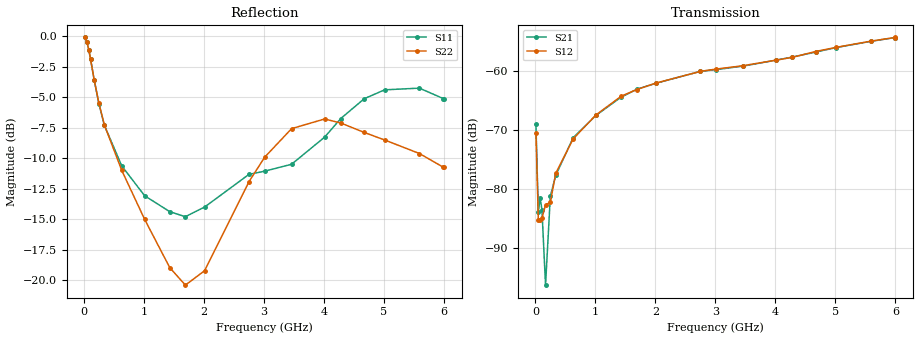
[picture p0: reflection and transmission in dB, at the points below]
!Agilent Technologies,N5230A,MY45001650,A.07.50.48
!Agilent N5230A: A.07.50.48
!Date: Saturday, July 08, 2017 15:48:11
!Correction: S11(Full 2 Port(1,2))
!S21(Full 2 Port(1,2))
!S12(Full 2 Port(1,2))
!S22(Full 2 Port(1,2))
!S2P File: Measurements: S11, S21, S12, S22:
# Hz S  dB  R 50
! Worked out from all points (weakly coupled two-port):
!   600 points, 10 MHz to 6 GHz, reference 50 ohm
!   highest |S21| = -54.43 dB at 5.99 GHz (marker M1); lowest = -96.3 dB at 170 MHz (marker M2)
!   lowest |S11| = -14.8 dB at 1.69 GHz (marker M3), VSWR 1.44, Z = 34.7 + j1.18 ohm
!   |S11| at or under -10 dB: 553.2 MHz to 3.662 GHz (3.109 GHz wide, 148 % of centre)
!   |S22| runs from -20.6 to -0.1 dB; largest |S21 - S12| = 0.00047
!   S11 on the Smith chart (normalised r, x): 10 MHz: 3, -20; 110 MHz: 0.52, -1.89; 340 MHz: 0.55, -0.54; 2.75 GHz: 0.58, +0.10; 4.28 GHz: 1.39, +1.16; 6 GHz: 2.58, -1.44
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1e7  -0.11 -5.7  -69.07 -174.8  -70.48 -81.6  -0.11 -5.7
5e7  -0.50 -26.6  -83.99 138.6  -85.29 -8.4  -0.50 -26.5
8e7  -1.13 -40.8  -81.49 137.6  -85.32 8.5  -1.12 -40.5
1.1e8  -1.91 -53.1  -83.53 99.7  -85.00 -21.4  -1.91 -52.8
1.7e8  -3.61 -73.0  -96.27 110.6  -82.67 103.9  -3.59 -72.6
2.5e8  -5.58 -92.8  -81.23 110.4  -82.28 106.8  -5.53 -92.3
3.4e8  -7.32 -110.7  -77.72 91.1  -77.37 86.9  -7.29 -108.9
6.3e8  -10.65 -147.5  -71.35 52.8  -71.55 54.3  -11.02 -142.3
1.01e9  -13.09 -172.4  -67.58 13.9  -67.50 13.8  -15.02 -165.4
1.43e9  -14.40 174.0  -64.49 -23.9  -64.34 -22.4  -18.99 -179.9
1.69e9  -14.81 174.8  -63.17 -48.4  -63.21 -47.2  -20.42 -177.7
2.01e9  -14.02 177.0  -62.14 -77.8  -62.12 -78.2  -19.24 -174.7
2.75e9  -11.34 162.4  -60.14 -148.3  -60.14 -147.9  -11.94 162.5
3.01e9  -11.08 149.1  -59.84 -172.8  -59.75 -172.8  -9.94 152.6
3.46e9  -10.51 117.0  -59.25 146.0  -59.18 146.2  -7.59 138.1
4.01e9  -8.29 64.4  -58.24 98.9  -58.24 98.9  -6.80 119.1
4.28e9  -6.76 45.4  -57.72 78.0  -57.77 78.2  -7.13 108.3
4.67e9  -5.14 25.4  -56.88 46.4  -56.78 46.2  -7.90 89.1
5.01e9  -4.41 13.6  -56.12 19.0  -56.08 18.6  -8.52 69.3
5.59e9  -4.27 -4.6  -55.06 -28.3  -55.03 -28.4  -9.63 32.5
5.99e9  -5.13 -20.0  -54.43 -55.8  -54.41 -56.0  -10.76 10.4
6e9  -5.13 -20.5  -54.44 -56.9  -54.39 -56.5  -10.77 9.6
